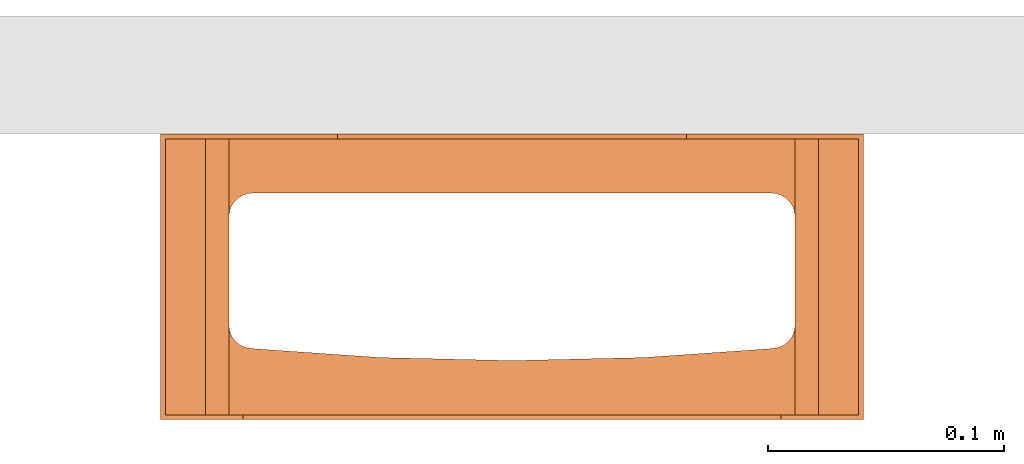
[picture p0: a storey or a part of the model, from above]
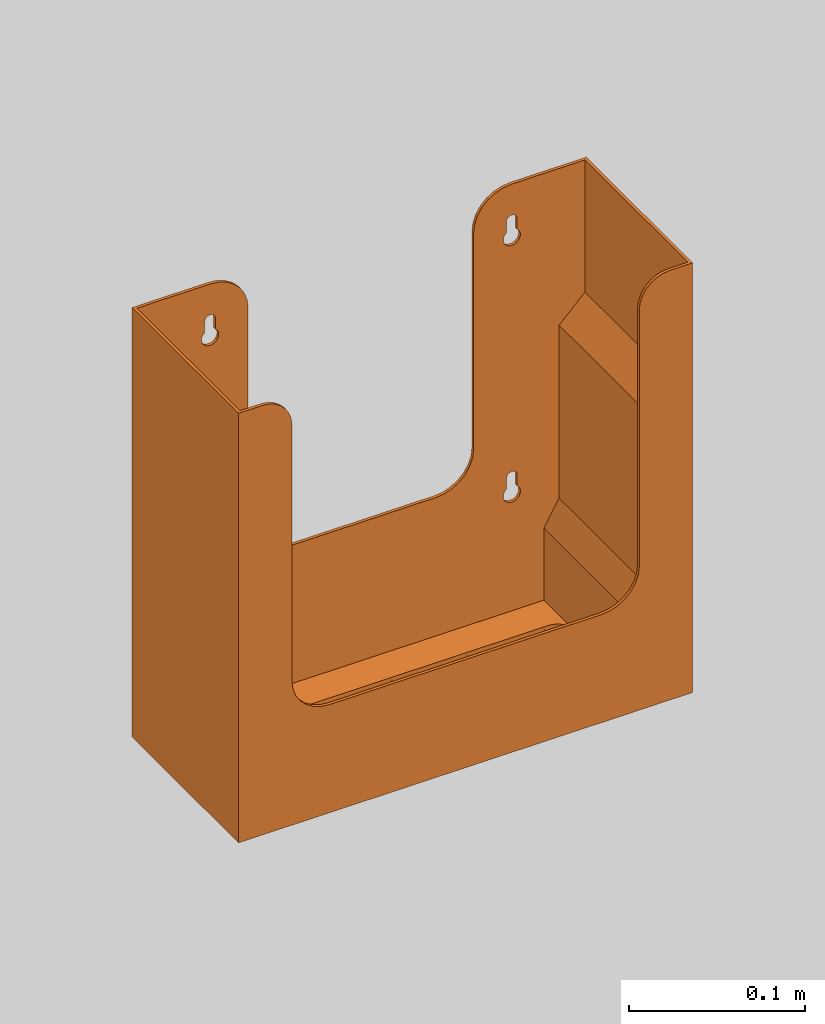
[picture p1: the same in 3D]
Properties of the parts of a building model (IFC2X3)

# File
Description: ViewDefinition [CoordinationView]
Time: 2018-10-29T17:13:34
Written by: The EXPRESS Data Manager Version 5.01.0100.02.64mod : 6 Jun 2012
Made in: 20140709_2115(x64) - Exporter 2014.0.2014.0709 - Default UI
Comment: STEP Physical File produced by: The EXPRESS Data Manager Version 5.01.0100.02.64mod : 6 Jun 2012 * Module: EDMstepFileFactory/EDMstandAlone * Creation date: Mon Oct 29 17:13:34 2018 * Host: BIM-HP * Database: C:\Users\dcole\AppData\Local\Temp\{8A916901-997C-401A-BC9B-58024EF99FDE}\ifc * Database version: 5507 * Database creation date: Mon Oct 29 17:13:32 2018 * Schema: IFC2X3 * Model: DataRepository.ifc * Model creation date: Mon Oct 29 17:13:32 2018 * Header model: DataRepository.ifc_HeaderModel * Header model creation date: Mon Oct 29 17:13:33 2018 * EDMuser: sdai-user * EDMgroup: sdai-group * License ID and type: 5605 : Permanent license. Expiry date: * EDMstepFileFactory options: 020000

# IfcProject
LongName: P:\Fastrack\53721_DOLPHIN SOLUTIONS LIMITED\ADDITIONAL DRAWINGS 2018 BIM\IFC\DP3502.ifc

# IfcSite, Default
RefLatitude: 42, 24, 53, 508911; RefLongitude: -71, -15, -29, -58837; RefElevation: 0 mm

# IfcBuilding
Pset_BuildingCommon - NumberOfStoreys: 1

# IfcBuildingStorey, Level 1
LongName: Level 1; Elevation: 0 mm
Constraints - Elevation Base: Project Base Point; Elevation: 0 mm
Graphics - Line Pattern: -3000010; Symbol at End 2 Default: yes; Color: 0; Line Weight: 1; Symbol at End 1 Default: no
Identity Data - Building Story: yes; Structural: no; Name: Level 1
Dimensions - Computation Height: 0 mm

# IfcBuildingElementProxy: DP3502 Dolphin Paper Towel Dispenser for Mounting Behind Mirror, DP3502:DP3502 Dolphin Paper Towel Dispenser for Mounting Behind Mirror:78323
In: Level 1
Constraints - Level: Level: Level 1; Moves With Nearby Elements: no; Offset: 357.907 mm; Host: Level : Level 1
Phasing - Phase Created: New Construction
Dimensions - Volume: 0.00132057 m3; Width: 298mm; Projection: 121mm; Capacity Paper Towels: 500; Height: 298mm
Pset_ManufacturerTypeInformation - Manufacturer: Bell-Chem Products Co. Ltd.
Pset_BuildingElementProxyCommon - Reference: DP3502 Dolphin Paper Towel Dispenser for Mounting Behind Mirror
Identity Data - Address: Southpoint, Compass Park, Bodiam, Robertsbridge, TN32 5BS; Description: Paper towel dispenser for mounting behind mirror; Email: info@dolphindispenser.co.uk; Assembly Description: Misc. Other Plumbing Systems; Tel No.: +44 (0) 1424 202224; Assembly Code: D2090900; Fax No.: +44 (0) 1424 205200; URL: www.dolphindispensers.co.uk; Manufacturer: Bell-Chem Products Co. Ltd.; Model: DP3502
General - Product Page Link: http://www.dolphindispensers.co.uk/en/product/paper-towel-dispenser-for-mounting-behind-mirror; Product Data: Superiour quality and timless design for prestigious washrooms. Full metal housing in robust, easy-to-clean stainless steel AISI 304. Holds approx 500 paper towels. For mounting in a cabinet on site, refillable from the top. Designed to be fitted behind a hinged mirror.

# IfcOpeningElement: Opening, DP3502:DP3502 Dolphin Paper Towel Dispenser for Mounting Behind Mirror:78323:1
In: Level 1
Constraints - Level: Level: Level 1; Moves With Nearby Elements: no; Offset: 357.907 mm; Host: Level : Level 1
Phasing - Phase Created: New Construction
Dimensions - Volume: 0.00132057 m3; Width: 298mm; Projection: 121mm; Capacity Paper Towels: 500; Height: 298mm
Pset_ManufacturerTypeInformation - Manufacturer: Bell-Chem Products Co. Ltd.
Identity Data - Address: Southpoint, Compass Park, Bodiam, Robertsbridge, TN32 5BS; Description: Paper towel dispenser for mounting behind mirror; Email: info@dolphindispenser.co.uk; Assembly Description: Misc. Other Plumbing Systems; Tel No.: +44 (0) 1424 202224; Assembly Code: D2090900; Fax No.: +44 (0) 1424 205200; URL: www.dolphindispensers.co.uk; Manufacturer: Bell-Chem Products Co. Ltd.; Model: DP3502
General - Product Page Link: http://www.dolphindispensers.co.uk/en/product/paper-towel-dispenser-for-mounting-behind-mirror; Product Data: Superiour quality and timless design for prestigious washrooms. Full metal housing in robust, easy-to-clean stainless steel AISI 304. Holds approx 500 paper towels. For mounting in a cabinet on site, refillable from the top. Designed to be fitted behind a hinged mirror.

# IfcWallStandardCase: Basic Wall:Wall 1, Basic Wall:Wall 1:3092
In: Level 1
Type - PredefinedType: STANDARD; Material: Default Wall 50 mm
Type - Construction - Wrapping at Inserts: Do not wrap; Width: 50 mm; Function: Exterior
Type - Analytical Properties - Roughness: 1; Absorptance: 0.1
Type - Graphics - Coarse Scale Fill Color: 8454143
Constraints - Location Line: Finish Face: Interior; Top Extension Distance: 0 mm; Base Offset: 0 mm; Top Offset: 0 mm; Related to Mass: no; Top is Attached: no; Base is Attached: no; Base Extension Distance: 0 mm; Room Bounding: yes; Base Constraint: Level: Level 1; Unconnected Height: 936.967 mm
Dimensions - Area: 0.599659 m2; Length: 640 mm; Volume: 0.0299829 m3
Phasing - Phase Created: New Construction
Structural - Structural: no; Structural Usage: Non-bearing; Enable Analytical Model: no
Pset_WallCommon - Reference: Wall 1; LoadBearing: no; ExtendToStructure: no; IsExternal: yes
